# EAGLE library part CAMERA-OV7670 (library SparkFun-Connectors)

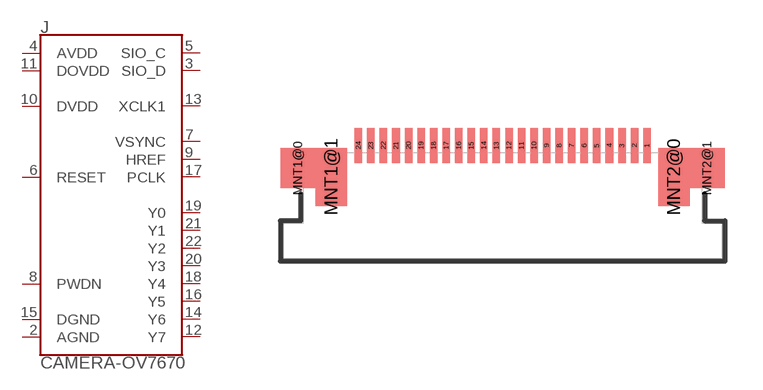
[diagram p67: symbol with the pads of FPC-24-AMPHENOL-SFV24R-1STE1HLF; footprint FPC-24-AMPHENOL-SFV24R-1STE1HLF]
Designator prefix J

## CAMERA-OV7670 (DIGIKEY: 609-4320-2-ND; PROD_ID: CONN-14233)  [FPC-24-AMPHENOL-SFV24R-1STE1HLF]
2  AGND
3  SIO_D
4  AVDD
5  SIO_C
6  RESET
7  VSYNC
8  PWDN
9  HREF
10  DVDD
11  DOVDD
12  Y7
13  XCLK1
14  Y6
15  DGND
16  Y5
17  PCLK
18  Y4
19  Y0
20  Y3
21  Y1
22  Y2
MNT1@0  MNT1
MNT1@1  MNT1
MNT2@0  MNT2
MNT2@1  MNT2

## Footprint FPC-24-AMPHENOL-SFV24R-1STE1HLF (pad centres in mm)
24-Pin FPC/FFC Connector - 0.5mm pitch Digikey: 609-4320-2-ND Datasheet
smd 0.3 x 1.4: 1 5.75,2.4; 2 5.25,2.4; 3 4.75,2.4; 4 4.25,2.4; 5 3.75,2.4; 6 3.25,2.4; 7 2.75,2.4; 8 2.25,2.4; 9 1.75,2.4; 10 1.25,2.4; 11 0.75,2.4; 12 0.25,2.4; 13 -0.25,2.4; 14 -0.75,2.4; 15 -1.25,2.4; 16 -1.75,2.4; 17 -2.25,2.4; 18 -2.75,2.4; 19 -3.25,2.4; 20 -3.75,2.4; 21 -4.25,2.4; 22 -4.75,2.4; 23 -5.25,2.4; 24 -5.75,2.4
smd 1.4 x 1.6: MNT1@0 -8.15,1.5; MNT2@1 8.15,1.5
smd 1.25 x 2.3: MNT1@1 -6.825,1.15; MNT2@0 6.825,1.15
